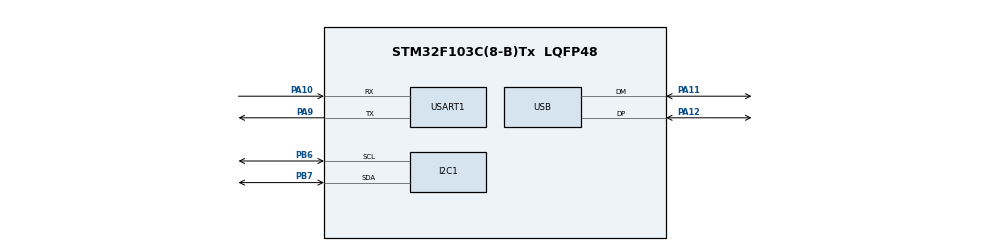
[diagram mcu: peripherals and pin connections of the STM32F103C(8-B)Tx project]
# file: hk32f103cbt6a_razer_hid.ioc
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Mcu.Family=STM32F1
Mcu.Name=STM32F103C(8-B)Tx
Mcu.Package=LQFP48
NVIC.PriorityGroup=NVIC_PRIORITYGROUP_4
NVIC.USART1_IRQn=true\:0\:0\:false\:false\:true\:true\:true\:true
NVIC.USB_LP_CAN1_RX0_IRQn=true\:0\:0\:false\:false\:true\:false\:true\:true
PA10.Mode=Asynchronous
PA10.Signal=USART1_RX
PA11.Mode=Device
PA11.Signal=USB_DM
PA12.Mode=Device
PA12.Signal=USB_DP
PA13.Mode=Serial_Wire
PA13.Signal=SYS_JTMS-SWDIO
PA14.Mode=Serial_Wire
PA14.Signal=SYS_JTCK-SWCLK
PA9.Mode=Asynchronous
PA9.Signal=USART1_TX
PB6.Mode=I2C
PB6.Signal=I2C1_SCL
PB7.Mode=I2C
PB7.Signal=I2C1_SDA
PD0-OSC_IN.Mode=HSE-External-Oscillator
PD0-OSC_IN.Signal=RCC_OSC_IN
PD1-OSC_OUT.Mode=HSE-External-Oscillator
PD1-OSC_OUT.Signal=RCC_OSC_OUT
ProjectManager.HeapSize=0x600
ProjectManager.StackSize=0x400
ProjectManager.TargetToolchain=MDK-ARM V5.32
RCC.AHBFreq_Value=72000000
RCC.APB1CLKDivider=RCC_HCLK_DIV2
RCC.APB1Freq_Value=36000000
RCC.APB1TimFreq_Value=72000000
RCC.APB2Freq_Value=72000000
RCC.APB2TimFreq_Value=72000000
RCC.HCLKFreq_Value=72000000
RCC.PLLMUL=RCC_PLL_MUL9
RCC.SYSCLKFreq_VALUE=72000000
RCC.SYSCLKSource=RCC_SYSCLKSOURCE_PLLCLK
RCC.USBFreq_Value=48000000
RCC.USBPrescaler=RCC_USBCLKSOURCE_PLL_DIV1_5
USART1.VirtualMode=VM_ASYNC
USB_DEVICE.CLASS_NAME_FS=CUSTOM_HID
USB_DEVICE.CUSTOM_HID_FS_BINTERVAL=0x1
USB_DEVICE.USBD_CUSTOMHID_OUTREPORT_BUF_SIZE=64
USB_DEVICE.USBD_CUSTOM_HID_REPORT_DESC_SIZE=33
USB_DEVICE.VirtualMode=CustomHid
USB_DEVICE.VirtualModeFS=Custom_Hid_FS
VP_USB_DEVICE_VS_USB_DEVICE_CUSTOM_HID_FS.Mode=CUSTOM_HID_FS
board=custom

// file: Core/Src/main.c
/* USER CODE BEGIN Header */
/**
  ******************************************************************************
  * @file           : main.c
  * @brief          : Main program body
  ******************************************************************************
  * @attention
  *
  * Copyright (c) 2023 STMicroelectronics.
  * All rights reserved.
  *
  * This software is licensed under terms that can be found in the LICENSE file
  * in the root directory of this software component.
  * If no LICENSE file comes with this software, it is provided AS-IS.
  *
  ******************************************************************************
  */
/* USER CODE END Header */
#include "main.h"
#include "i2c.h"
#include "usart.h"
#include "usb_device.h"
#include "gpio.h"
#include "IS3xFL323x.h"
/* USER CODE BEGIN Includes */
#include "usbd_custom_hid_if.h"
#include "usbd_customhid.h" //包括发送函数头文件

/* USER CODE END Includes */

/* USER CODE BEGIN PD */
#define USER_MAIN_DEBUG

#ifdef USER_MAIN_DEBUG
#define user_main_printf(format, ...) printf( format "\r\n",##__VA_ARGS__)
#define user_main_info(format, ...)   printf("main.info:" format "\r\n",##__VA_ARGS__)
#define user_main_debug(format, ...)  printf("main.debug:" format "\r\n",##__VA_ARGS__)
#define user_main_error(format, ...)  printf("main.error:" format "\r\n",##__VA_ARGS__)
#else
#define user_main_printf(format, ...)
#define user_main_info(format, ...)
#define user_main_debug(format, ...)
#define user_main_error(format, ...)
#endif
/* USER CODE END PD */

/* USER CODE BEGIN PV */
extern USBD_HandleTypeDef hUsbDeviceFS; //外部声明USB的句柄
extern unsigned char USB_Recive_Buffer[64]; //USB接收缓存
extern unsigned char USB_Received_Count;//USB接收数据计数
/* USER CODE END PV */

void SystemClock_Config(void);

int main(void)
{

  /* MCU Configuration--------------------------------------------------------*/

  /* Reset of all peripherals, Initializes the Flash interface and the Systick. */
  HAL_Init();

  /* Configure the system clock */
  SystemClock_Config();

  /* Initialize all configured peripherals */
  MX_GPIO_Init();
  MX_I2C1_Init();
  MX_USART1_UART_Init();
  //MX_USB_DEVICE_Init();
  /* USER CODE BEGIN 2 */
  IS3xFL323x_Init();
  /* USER CODE END 2 */

  /* Infinite loop */
  while (1)
  {
      printf("Enter main while loop!\r\n");
      user_main_debug("Main debug!\n");
      //USBD_CUSTOM_HID_SendReport(&hUsbDeviceFS, USB_Recive_Buffer, 64);
      IS3xFL323x_Flow();
      IS3xFL323x_ALL_ON();
      HAL_Delay(500);
      //HAL_I2C_Master_Transmit(&hi2c1,0x78,,2,20)
      //HAL_GPIO_WritePin(LED1_GPIO_Port,LED1_Pin,GPIO_PIN_RESET);
      //HAL_Delay(500);
      //HAL_GPIO_WritePin(LED1_GPIO_Port,LED1_Pin,GPIO_PIN_SET);
      //HAL_Delay(500);
  }
}

// void SystemClock_Config(void)
// {
//   RCC_OscInitTypeDef RCC_OscInitStruct = {0};
//   RCC_ClkInitTypeDef RCC_ClkInitStruct = {0};
//   RCC_PeriphCLKInitTypeDef PeriphClkInit = {0};

//   /** Initializes the RCC Oscillators according to the specified parameters
//   * in the RCC_OscInitTypeDef structure.
//   */
//   RCC_OscInitStruct.OscillatorType = RCC_OSCILLATORTYPE_HSE;
//   RCC_OscInitStruct.HSEState = RCC_HSE_ON;
//   RCC_OscInitStruct.HSEPredivValue = RCC_HSE_PREDIV_DIV1;
//   RCC_OscInitStruct.HSIState = RCC_HSI_ON;
//   RCC_OscInitStruct.PLL.PLLState = RCC_PLL_ON;
//   RCC_OscInitStruct.PLL.PLLSource = RCC_PLLSOURCE_HSE;
//   RCC_OscInitStruct.PLL.PLLMUL = RCC_PLL_MUL9;
//   if (HAL_RCC_OscConfig(&RCC_OscInitStruct) != HAL_OK)
//   {
//     Error_Handler();
//   }

//   /** Initializes the CPU, AHB and APB buses clocks
//   */
//   RCC_ClkInitStruct.ClockType = RCC_CLOCKTYPE_HCLK|RCC_CLOCKTYPE_SYSCLK
//                               |RCC_CLOCKTYPE_PCLK1|RCC_CLOCKTYPE_PCLK2;
//   RCC_ClkInitStruct.SYSCLKSource = RCC_SYSCLKSOURCE_PLLCLK;
//   RCC_ClkInitStruct.AHBCLKDivider = RCC_SYSCLK_DIV1;
//   RCC_ClkInitStruct.APB1CLKDivider = RCC_HCLK_DIV2;
//   RCC_ClkInitStruct.APB2CLKDivider = RCC_HCLK_DIV1;

//   if (HAL_RCC_ClockConfig(&RCC_ClkInitStruct, FLASH_LATENCY_2) != HAL_OK)
//   {
//     Error_Handler();
//   }
//   PeriphClkInit.PeriphClockSelection = RCC_PERIPHCLK_USB;
//   PeriphClkInit.UsbClockSelection = RCC_USBCLKSOURCE_PLL_DIV1_5;
//   if (HAL_RCCEx_PeriphCLKConfig(&PeriphClkInit) != HAL_OK)
//   {
//     Error_Handler();
//   }
// }
void SystemClock_Config(void)
{
  RCC_OscInitTypeDef RCC_OscInitStruct = {0};
  RCC_ClkInitTypeDef RCC_ClkInitStruct = {0};

  /** Initializes the RCC Oscillators according to the specified parameters
  * in the RCC_OscInitTypeDef structure.
  */
  RCC_OscInitStruct.OscillatorType = RCC_OSCILLATORTYPE_HSI;
  RCC_OscInitStruct.HSIState = RCC_HSI_ON;
  RCC_OscInitStruct.HSICalibrationValue = RCC_HSICALIBRATION_DEFAULT;
  RCC_OscInitStruct.PLL.PLLState = RCC_PLL_ON;
  RCC_OscInitStruct.PLL.PLLSource = RCC_PLLSOURCE_HSI_DIV2;
  RCC_OscInitStruct.PLL.PLLMUL = RCC_PLL_MUL12;
  if (HAL_RCC_OscConfig(&RCC_OscInitStruct) != HAL_OK)
  {
    Error_Handler();
  }

  /** Initializes the CPU, AHB and APB buses clocks
  */
  RCC_ClkInitStruct.ClockType = RCC_CLOCKTYPE_HCLK|RCC_CLOCKTYPE_SYSCLK
                              |RCC_CLOCKTYPE_PCLK1|RCC_CLOCKTYPE_PCLK2;
  RCC_ClkInitStruct.SYSCLKSource = RCC_SYSCLKSOURCE_PLLCLK;
  RCC_ClkInitStruct.AHBCLKDivider = RCC_SYSCLK_DIV1;
  RCC_ClkInitStruct.APB1CLKDivider = RCC_HCLK_DIV2;
  RCC_ClkInitStruct.APB2CLKDivider = RCC_HCLK_DIV1;

  if (HAL_RCC_ClockConfig(&RCC_ClkInitStruct, FLASH_LATENCY_1) != HAL_OK)
  {
    Error_Handler();
  }
}

void Error_Handler(void)
{
  __disable_irq();
  while (1)
  {
  }
}
